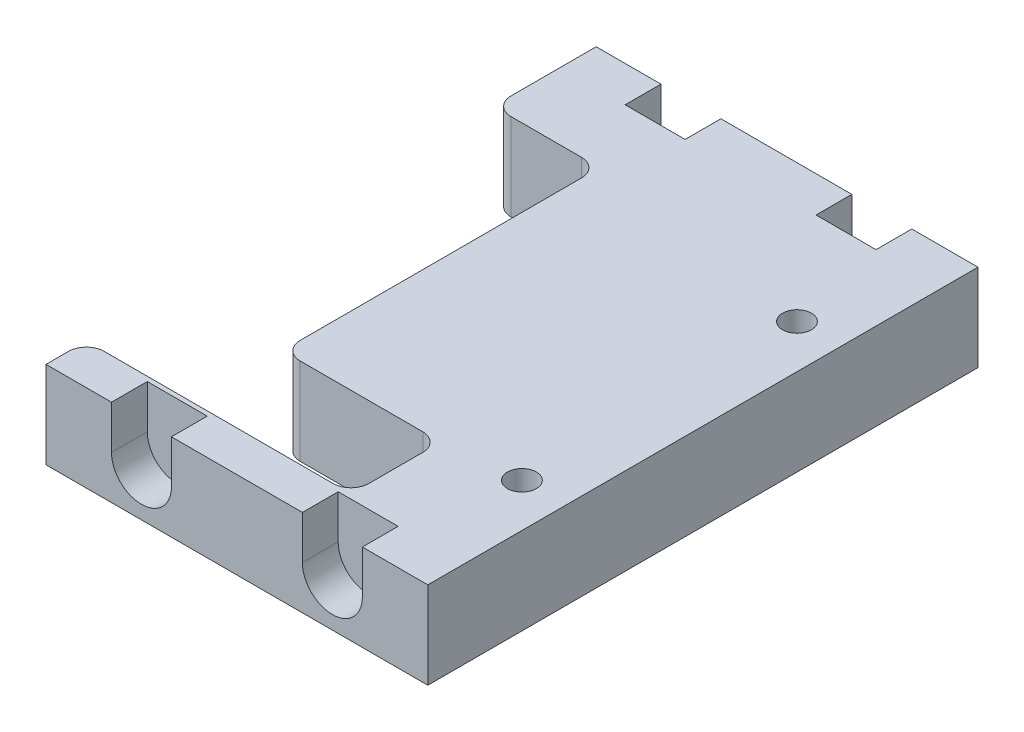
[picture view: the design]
ISO-10303-21;
HEADER;
FILE_DESCRIPTION(('STEP AP214'),'2;1');
FILE_NAME('part.step','',(''),(''),'','','');
FILE_SCHEMA(('AUTOMOTIVE_DESIGN { 1 0 10303 214 1 1 1 1 }'));
ENDSEC;
DATA;
#1=APPLICATION_CONTEXT('core data for automotive mechanical design processes');
#2=APPLICATION_PROTOCOL_DEFINITION('international standard','automotive_design',2000,#1);
#3=PRODUCT_CONTEXT('',#1,'mechanical');
#4=PRODUCT('Part','Part','',(#3));
#5=PRODUCT_RELATED_PRODUCT_CATEGORY('part','',(#4));
#6=PRODUCT_DEFINITION_FORMATION('','',#4);
#7=PRODUCT_DEFINITION_CONTEXT('part definition',#1,'design');
#8=PRODUCT_DEFINITION('design','',#6,#7);
#9=PRODUCT_DEFINITION_SHAPE('','',#8);
#10=(LENGTH_UNIT() NAMED_UNIT(*) SI_UNIT(.MILLI.,.METRE.));
#11=(NAMED_UNIT(*) PLANE_ANGLE_UNIT() SI_UNIT($,.RADIAN.));
#12=(NAMED_UNIT(*) SI_UNIT($,.STERADIAN.) SOLID_ANGLE_UNIT());
#13=UNCERTAINTY_MEASURE_WITH_UNIT(LENGTH_MEASURE(1.E-05),#10,'distance_accuracy_value','');
#14=(GEOMETRIC_REPRESENTATION_CONTEXT(3) GLOBAL_UNCERTAINTY_ASSIGNED_CONTEXT((#13)) GLOBAL_UNIT_ASSIGNED_CONTEXT((#10,
#11,#12)) REPRESENTATION_CONTEXT('',''));
#15=CARTESIAN_POINT('',(0.,0.,0.));
#16=DIRECTION('',(0.,0.,1.));
#17=DIRECTION('',(1.,0.,0.));
#18=AXIS2_PLACEMENT_3D('',#15,#16,#17);
#19=CARTESIAN_POINT('',(-654.083526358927,561.091856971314,0.));
#20=DIRECTION('',(0.,1.,0.));
#21=DIRECTION('',(0.,0.,1.));
#22=AXIS2_PLACEMENT_3D('',#19,#20,#21);
#23=PLANE('',#22);
#24=CARTESIAN_POINT('',(-726.128429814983,561.091856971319,-58.5596999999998));
#25=DIRECTION('',(0.,-1.,0.));
#26=DIRECTION('',(0.,0.,-1.));
#27=AXIS2_PLACEMENT_3D('',#24,#25,#26);
#28=CIRCLE('',#27,2.05000000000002);
#29=CARTESIAN_POINT('',(-726.128429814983,561.091856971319,-60.6096999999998));
#30=VERTEX_POINT('',#29);
#31=EDGE_CURVE('E428',#30,#30,#28,.F.);
#32=ORIENTED_EDGE('',*,*,#31,.F.);
#33=EDGE_LOOP('',(#32));
#34=FACE_BOUND('',#33,.T.);
#35=CARTESIAN_POINT('',(-726.128429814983,561.091856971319,-19.5198999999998));
#36=DIRECTION('',(0.,-1.,0.));
#37=DIRECTION('',(0.,0.,-1.));
#38=AXIS2_PLACEMENT_3D('',#35,#36,#37);
#39=CIRCLE('',#38,2.05000000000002);
#40=CARTESIAN_POINT('',(-726.128429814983,561.091856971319,-21.5698999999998));
#41=VERTEX_POINT('',#40);
#42=EDGE_CURVE('E392',#41,#41,#39,.F.);
#43=ORIENTED_EDGE('',*,*,#42,.F.);
#44=EDGE_LOOP('',(#43));
#45=FACE_BOUND('',#44,.T.);
#46=DIRECTION('',(1.,0.,0.));
#47=VECTOR('',#46,1.);
#48=CARTESIAN_POINT('',(-654.083526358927,561.091856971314,-78.0796));
#49=LINE('',#48,#47);
#50=CARTESIAN_POINT('',(-756.444899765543,561.091856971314,-78.0796));
#51=VERTEX_POINT('',#50);
#52=CARTESIAN_POINT('',(-737.859519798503,561.091856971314,-78.0796));
#53=VERTEX_POINT('',#52);
#54=EDGE_CURVE('E486',#51,#53,#49,.T.);
#55=ORIENTED_EDGE('',*,*,#54,.F.);
#56=DIRECTION('',(0.,0.,-1.));
#57=VECTOR('',#56,1.);
#58=CARTESIAN_POINT('',(-756.444899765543,561.091856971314,-72.9996));
#59=LINE('',#58,#57);
#60=CARTESIAN_POINT('',(-756.444899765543,561.091856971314,-72.9996));
#61=VERTEX_POINT('',#60);
#62=EDGE_CURVE('E340',#61,#51,#59,.T.);
#63=ORIENTED_EDGE('',*,*,#62,.F.);
#64=DIRECTION('',(1.,0.,0.));
#65=VECTOR('',#64,1.);
#66=CARTESIAN_POINT('',(0.,561.091856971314,-72.9996));
#67=LINE('',#66,#65);
#68=CARTESIAN_POINT('',(-764.953899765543,561.091856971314,-72.9996));
#69=VERTEX_POINT('',#68);
#70=EDGE_CURVE('E317',#69,#61,#67,.T.);
#71=ORIENTED_EDGE('',*,*,#70,.F.);
#72=DIRECTION('',(0.,0.,-1.));
#73=VECTOR('',#72,1.);
#74=CARTESIAN_POINT('',(-764.953899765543,561.091856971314,-72.9996));
#75=LINE('',#74,#73);
#76=CARTESIAN_POINT('',(-764.953899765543,561.091856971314,-78.0796));
#77=VERTEX_POINT('',#76);
#78=EDGE_CURVE('E312',#69,#77,#75,.T.);
#79=ORIENTED_EDGE('',*,*,#78,.T.);
#80=CARTESIAN_POINT('',(-774.144989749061,561.091856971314,-78.0796));
#81=VERTEX_POINT('',#80);
#82=EDGE_CURVE('E482',#81,#77,#49,.T.);
#83=ORIENTED_EDGE('',*,*,#82,.F.);
#84=DIRECTION('',(0.,0.,1.));
#85=VECTOR('',#84,1.);
#86=CARTESIAN_POINT('',(-774.144989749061,561.091856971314,0.));
#87=LINE('',#86,#85);
#88=CARTESIAN_POINT('',(-774.144989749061,561.091856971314,-65.9929986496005));
#89=VERTEX_POINT('',#88);
#90=EDGE_CURVE('E487',#81,#89,#87,.T.);
#91=ORIENTED_EDGE('',*,*,#90,.T.);
#92=CARTESIAN_POINT('',(-771.604989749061,561.091856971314,-65.9929986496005));
#93=DIRECTION('',(0.,1.,0.));
#94=DIRECTION('',(0.,0.,1.));
#95=AXIS2_PLACEMENT_3D('',#92,#93,#94);
#96=CIRCLE('',#95,2.54);
#97=CARTESIAN_POINT('',(-771.604989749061,561.091856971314,-63.4529986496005));
#98=VERTEX_POINT('',#97);
#99=EDGE_CURVE('E551',#89,#98,#96,.T.);
#100=ORIENTED_EDGE('',*,*,#99,.T.);
#101=DIRECTION('',(-1.,0.,0.));
#102=VECTOR('',#101,1.);
#103=CARTESIAN_POINT('',(0.,561.091856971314,-63.4529986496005));
#104=LINE('',#103,#102);
#105=CARTESIAN_POINT('',(-761.598172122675,561.091856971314,-63.4529986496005));
#106=VERTEX_POINT('',#105);
#107=EDGE_CURVE('E441',#106,#98,#104,.T.);
#108=ORIENTED_EDGE('',*,*,#107,.F.);
#109=CARTESIAN_POINT('',(-761.598172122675,561.091856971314,-60.9129986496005));
#110=DIRECTION('',(0.,1.,0.));
#111=DIRECTION('',(0.,0.,1.));
#112=AXIS2_PLACEMENT_3D('',#109,#110,#111);
#113=CIRCLE('',#112,2.54);
#114=CARTESIAN_POINT('',(-759.058172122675,561.091856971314,-60.9129986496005));
#115=VERTEX_POINT('',#114);
#116=EDGE_CURVE('E558',#106,#115,#113,.F.);
#117=ORIENTED_EDGE('',*,*,#116,.T.);
#118=DIRECTION('',(0.,0.,1.));
#119=VECTOR('',#118,1.);
#120=CARTESIAN_POINT('',(-759.058172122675,561.091856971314,0.));
#121=LINE('',#120,#119);
#122=CARTESIAN_POINT('',(-759.058172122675,561.091856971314,-20.995433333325));
#123=VERTEX_POINT('',#122);
#124=EDGE_CURVE('E435',#115,#123,#121,.T.);
#125=ORIENTED_EDGE('',*,*,#124,.T.);
#126=CARTESIAN_POINT('',(-756.518172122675,561.091856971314,-20.995433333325));
#127=DIRECTION('',(0.,1.,0.));
#128=DIRECTION('',(0.,0.,1.));
#129=AXIS2_PLACEMENT_3D('',#126,#127,#128);
#130=CIRCLE('',#129,2.54);
#131=CARTESIAN_POINT('',(-756.518172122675,561.091856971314,-18.455433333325));
#132=VERTEX_POINT('',#131);
#133=EDGE_CURVE('E519',#123,#132,#130,.T.);
#134=ORIENTED_EDGE('',*,*,#133,.T.);
#135=DIRECTION('',(-1.,0.,0.));
#136=VECTOR('',#135,1.);
#137=CARTESIAN_POINT('',(0.,561.091856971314,-18.455433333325));
#138=LINE('',#137,#136);
#139=CARTESIAN_POINT('',(-739.131574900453,561.091856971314,-18.455433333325));
#140=VERTEX_POINT('',#139);
#141=EDGE_CURVE('E437',#140,#132,#138,.T.);
#142=ORIENTED_EDGE('',*,*,#141,.F.);
#143=CARTESIAN_POINT('',(-739.131574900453,561.091856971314,-15.915433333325));
#144=DIRECTION('',(0.,1.,0.));
#145=DIRECTION('',(0.,0.,1.));
#146=AXIS2_PLACEMENT_3D('',#143,#144,#145);
#147=CIRCLE('',#146,2.54);
#148=CARTESIAN_POINT('',(-736.591574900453,561.091856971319,-15.915433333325));
#149=VERTEX_POINT('',#148);
#150=EDGE_CURVE('E536',#140,#149,#147,.F.);
#151=ORIENTED_EDGE('',*,*,#150,.T.);
#152=DIRECTION('',(0.,0.,-1.));
#153=VECTOR('',#152,1.);
#154=CARTESIAN_POINT('',(-736.591574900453,561.091856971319,0.));
#155=LINE('',#154,#153);
#156=CARTESIAN_POINT('',(-736.591574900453,561.091856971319,-8.26959999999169));
#157=VERTEX_POINT('',#156);
#158=EDGE_CURVE('E447',#157,#149,#155,.T.);
#159=ORIENTED_EDGE('',*,*,#158,.F.);
#160=CARTESIAN_POINT('',(-739.131574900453,561.091856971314,-8.26959999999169));
#161=DIRECTION('',(0.,1.,0.));
#162=DIRECTION('',(0.,0.,1.));
#163=AXIS2_PLACEMENT_3D('',#160,#161,#162);
#164=CIRCLE('',#163,2.54);
#165=CARTESIAN_POINT('',(-739.131574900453,561.091856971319,-5.72959999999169));
#166=VERTEX_POINT('',#165);
#167=EDGE_CURVE('E540',#157,#166,#164,.F.);
#168=ORIENTED_EDGE('',*,*,#167,.T.);
#169=DIRECTION('',(1.,0.,0.));
#170=VECTOR('',#169,1.);
#171=CARTESIAN_POINT('',(0.,561.091856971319,-5.72959999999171));
#172=LINE('',#171,#170);
#173=CARTESIAN_POINT('',(-771.604989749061,561.091856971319,-5.72959999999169));
#174=VERTEX_POINT('',#173);
#175=EDGE_CURVE('E452',#174,#166,#172,.T.);
#176=ORIENTED_EDGE('',*,*,#175,.F.);
#177=CARTESIAN_POINT('',(-771.604989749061,561.091856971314,-3.18959999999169));
#178=DIRECTION('',(0.,1.,0.));
#179=DIRECTION('',(0.,0.,1.));
#180=AXIS2_PLACEMENT_3D('',#177,#178,#179);
#181=CIRCLE('',#180,2.54);
#182=CARTESIAN_POINT('',(-774.144989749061,561.091856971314,-3.18959999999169));
#183=VERTEX_POINT('',#182);
#184=EDGE_CURVE('E517',#174,#183,#181,.T.);
#185=ORIENTED_EDGE('',*,*,#184,.T.);
#186=CARTESIAN_POINT('',(-774.144989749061,561.091856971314,0.));
#187=VERTEX_POINT('',#186);
#188=EDGE_CURVE('E491',#183,#187,#87,.T.);
#189=ORIENTED_EDGE('',*,*,#188,.T.);
#190=DIRECTION('',(-1.,0.,0.));
#191=VECTOR('',#190,1.);
#192=CARTESIAN_POINT('',(-654.083526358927,561.091856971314,0.));
#193=LINE('',#192,#191);
#194=CARTESIAN_POINT('',(-764.852299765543,561.091856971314,0.));
#195=VERTEX_POINT('',#194);
#196=EDGE_CURVE('E472',#195,#187,#193,.T.);
#197=ORIENTED_EDGE('',*,*,#196,.F.);
#198=DIRECTION('',(0.,0.,1.));
#199=VECTOR('',#198,1.);
#200=CARTESIAN_POINT('',(-764.852299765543,561.091856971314,-5.08));
#201=LINE('',#200,#199);
#202=CARTESIAN_POINT('',(-764.852299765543,561.091856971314,-5.08));
#203=VERTEX_POINT('',#202);
#204=EDGE_CURVE('E421',#203,#195,#201,.T.);
#205=ORIENTED_EDGE('',*,*,#204,.F.);
#206=DIRECTION('',(-1.,0.,0.));
#207=VECTOR('',#206,1.);
#208=CARTESIAN_POINT('',(0.,561.091856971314,-5.08));
#209=LINE('',#208,#207);
#210=CARTESIAN_POINT('',(-756.343299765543,561.091856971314,-5.08));
#211=VERTEX_POINT('',#210);
#212=EDGE_CURVE('E406',#211,#203,#209,.T.);
#213=ORIENTED_EDGE('',*,*,#212,.F.);
#214=DIRECTION('',(0.,0.,1.));
#215=VECTOR('',#214,1.);
#216=CARTESIAN_POINT('',(-756.343299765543,561.091856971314,-5.08));
#217=LINE('',#216,#215);
#218=CARTESIAN_POINT('',(-756.343299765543,561.091856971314,0.));
#219=VERTEX_POINT('',#218);
#220=EDGE_CURVE('E423',#211,#219,#217,.T.);
#221=ORIENTED_EDGE('',*,*,#220,.T.);
#222=CARTESIAN_POINT('',(-737.757919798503,561.091856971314,0.));
#223=VERTEX_POINT('',#222);
#224=EDGE_CURVE('E481',#223,#219,#193,.T.);
#225=ORIENTED_EDGE('',*,*,#224,.F.);
#226=DIRECTION('',(0.,0.,1.));
#227=VECTOR('',#226,1.);
#228=CARTESIAN_POINT('',(-737.757919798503,561.091856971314,-5.08));
#229=LINE('',#228,#227);
#230=CARTESIAN_POINT('',(-737.757919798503,561.091856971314,-5.08));
#231=VERTEX_POINT('',#230);
#232=EDGE_CURVE('E393',#231,#223,#229,.T.);
#233=ORIENTED_EDGE('',*,*,#232,.F.);
#234=DIRECTION('',(-1.,0.,0.));
#235=VECTOR('',#234,1.);
#236=CARTESIAN_POINT('',(0.,561.091856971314,-5.08));
#237=LINE('',#236,#235);
#238=CARTESIAN_POINT('',(-729.248919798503,561.091856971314,-5.08));
#239=VERTEX_POINT('',#238);
#240=EDGE_CURVE('E374',#239,#231,#237,.T.);
#241=ORIENTED_EDGE('',*,*,#240,.F.);
#242=DIRECTION('',(0.,0.,1.));
#243=VECTOR('',#242,1.);
#244=CARTESIAN_POINT('',(-729.248919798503,561.091856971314,-5.08));
#245=LINE('',#244,#243);
#246=CARTESIAN_POINT('',(-729.248919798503,561.091856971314,0.));
#247=VERTEX_POINT('',#246);
#248=EDGE_CURVE('E395',#239,#247,#245,.T.);
#249=ORIENTED_EDGE('',*,*,#248,.T.);
#250=CARTESIAN_POINT('',(-719.95622981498,561.091856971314,-2.2204460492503E-13));
#251=VERTEX_POINT('',#250);
#252=EDGE_CURVE('E477',#251,#247,#193,.T.);
#253=ORIENTED_EDGE('',*,*,#252,.F.);
#254=DIRECTION('',(0.,0.,-1.));
#255=VECTOR('',#254,1.);
#256=CARTESIAN_POINT('',(-719.95622981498,561.091856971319,2.22044604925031E-13));
#257=LINE('',#256,#255);
#258=CARTESIAN_POINT('',(-719.95622981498,561.091856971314,-78.0796000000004));
#259=VERTEX_POINT('',#258);
#260=EDGE_CURVE('E461',#251,#259,#257,.T.);
#261=ORIENTED_EDGE('',*,*,#260,.T.);
#262=CARTESIAN_POINT('',(-729.350519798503,561.091856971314,-78.0796));
#263=VERTEX_POINT('',#262);
#264=EDGE_CURVE('E480',#263,#259,#49,.T.);
#265=ORIENTED_EDGE('',*,*,#264,.F.);
#266=DIRECTION('',(0.,0.,-1.));
#267=VECTOR('',#266,1.);
#268=CARTESIAN_POINT('',(-729.350519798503,561.091856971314,-72.9996));
#269=LINE('',#268,#267);
#270=CARTESIAN_POINT('',(-729.350519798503,561.091856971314,-72.9996));
#271=VERTEX_POINT('',#270);
#272=EDGE_CURVE('E362',#271,#263,#269,.T.);
#273=ORIENTED_EDGE('',*,*,#272,.F.);
#274=DIRECTION('',(1.,0.,0.));
#275=VECTOR('',#274,1.);
#276=CARTESIAN_POINT('',(0.,561.091856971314,-72.9996));
#277=LINE('',#276,#275);
#278=CARTESIAN_POINT('',(-737.859519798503,561.091856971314,-72.9996));
#279=VERTEX_POINT('',#278);
#280=EDGE_CURVE('E349',#279,#271,#277,.T.);
#281=ORIENTED_EDGE('',*,*,#280,.F.);
#282=DIRECTION('',(0.,0.,-1.));
#283=VECTOR('',#282,1.);
#284=CARTESIAN_POINT('',(-737.859519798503,561.091856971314,-72.9996));
#285=LINE('',#284,#283);
#286=EDGE_CURVE('E364',#279,#53,#285,.T.);
#287=ORIENTED_EDGE('',*,*,#286,.T.);
#288=EDGE_LOOP('',(#55,#63,#71,#79,#83,#91,#100,#108,#117,#125,#134,#142,#151,#159,#168,#176,
#185,#189,#197,#205,#213,#221,#225,#233,#241,#249,#253,#261,#265,#273,#281,#287));
#289=FACE_BOUND('',#288,.T.);
#290=ADVANCED_FACE('F94',(#34,#45,#289),#23,.T.);
#291=CARTESIAN_POINT('',(-1553.36997949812,0.,-78.0796));
#292=DIRECTION('',(0.,0.,-1.));
#293=DIRECTION('',(1.,0.,0.));
#294=AXIS2_PLACEMENT_3D('',#291,#292,#293);
#295=PLANE('',#294);
#296=CARTESIAN_POINT('',(-760.699399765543,554.919656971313,-78.0796));
#297=DIRECTION('',(0.,0.,-1.));
#298=DIRECTION('',(-1.,0.,0.));
#299=AXIS2_PLACEMENT_3D('',#296,#297,#298);
#300=CIRCLE('',#299,4.25450000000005);
#301=CARTESIAN_POINT('',(-764.953899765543,554.919656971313,-78.0796));
#302=VERTEX_POINT('',#301);
#303=CARTESIAN_POINT('',(-756.444899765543,554.919656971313,-78.0796));
#304=VERTEX_POINT('',#303);
#305=EDGE_CURVE('E110',#302,#304,#300,.F.);
#306=ORIENTED_EDGE('',*,*,#305,.T.);
#307=DIRECTION('',(0.,1.,0.));
#308=VECTOR('',#307,1.);
#309=CARTESIAN_POINT('',(-756.444899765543,0.,-78.0796));
#310=LINE('',#309,#308);
#311=EDGE_CURVE('E326',#304,#51,#310,.T.);
#312=ORIENTED_EDGE('',*,*,#311,.T.);
#313=ORIENTED_EDGE('',*,*,#54,.T.);
#314=DIRECTION('',(0.,-1.,0.));
#315=VECTOR('',#314,1.);
#316=CARTESIAN_POINT('',(-737.859519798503,0.,-78.0796));
#317=LINE('',#316,#315);
#318=CARTESIAN_POINT('',(-737.859519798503,554.919656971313,-78.0796));
#319=VERTEX_POINT('',#318);
#320=EDGE_CURVE('E356',#53,#319,#317,.T.);
#321=ORIENTED_EDGE('',*,*,#320,.T.);
#322=CARTESIAN_POINT('',(-733.605019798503,554.919656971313,-78.0796));
#323=DIRECTION('',(0.,0.,-1.));
#324=DIRECTION('',(-1.,0.,0.));
#325=AXIS2_PLACEMENT_3D('',#322,#323,#324);
#326=CIRCLE('',#325,4.25450000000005);
#327=CARTESIAN_POINT('',(-729.350519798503,554.919656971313,-78.0796));
#328=VERTEX_POINT('',#327);
#329=EDGE_CURVE('E118',#319,#328,#326,.F.);
#330=ORIENTED_EDGE('',*,*,#329,.T.);
#331=DIRECTION('',(0.,1.,0.));
#332=VECTOR('',#331,1.);
#333=CARTESIAN_POINT('',(-729.350519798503,0.,-78.0796));
#334=LINE('',#333,#332);
#335=EDGE_CURVE('E347',#328,#263,#334,.T.);
#336=ORIENTED_EDGE('',*,*,#335,.T.);
#337=ORIENTED_EDGE('',*,*,#264,.T.);
#338=DIRECTION('',(0.,1.,0.));
#339=VECTOR('',#338,1.);
#340=CARTESIAN_POINT('',(-719.956229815,2.51751805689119E-11,-78.0796));
#341=LINE('',#340,#339);
#342=CARTESIAN_POINT('',(-719.95622981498,548.747456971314,-78.0796));
#343=VERTEX_POINT('',#342);
#344=EDGE_CURVE('E465',#343,#259,#341,.T.);
#345=ORIENTED_EDGE('',*,*,#344,.F.);
#346=DIRECTION('',(1.,0.,0.));
#347=VECTOR('',#346,1.);
#348=CARTESIAN_POINT('',(0.,548.747456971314,-78.0796));
#349=LINE('',#348,#347);
#350=CARTESIAN_POINT('',(-774.144989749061,548.747456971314,-78.0796));
#351=VERTEX_POINT('',#350);
#352=EDGE_CURVE('E468',#351,#343,#349,.T.);
#353=ORIENTED_EDGE('',*,*,#352,.F.);
#354=DIRECTION('',(0.,-1.,0.));
#355=VECTOR('',#354,1.);
#356=CARTESIAN_POINT('',(-774.144989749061,562.158656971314,-78.0796));
#357=LINE('',#356,#355);
#358=EDGE_CURVE('E490',#81,#351,#357,.T.);
#359=ORIENTED_EDGE('',*,*,#358,.F.);
#360=ORIENTED_EDGE('',*,*,#82,.T.);
#361=DIRECTION('',(0.,-1.,0.));
#362=VECTOR('',#361,1.);
#363=CARTESIAN_POINT('',(-764.953899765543,0.,-78.0796));
#364=LINE('',#363,#362);
#365=EDGE_CURVE('E329',#77,#302,#364,.T.);
#366=ORIENTED_EDGE('',*,*,#365,.T.);
#367=EDGE_LOOP('',(#306,#312,#313,#321,#330,#336,#337,#345,#353,#359,#360,#366));
#368=FACE_BOUND('',#367,.T.);
#369=ADVANCED_FACE('F688',(#368),#295,.T.);
#370=CARTESIAN_POINT('',(-1553.36997949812,0.,0.));
#371=DIRECTION('',(0.,0.,1.));
#372=DIRECTION('',(-1.,0.,0.));
#373=AXIS2_PLACEMENT_3D('',#370,#371,#372);
#374=PLANE('',#373);
#375=CARTESIAN_POINT('',(-733.503419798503,554.919656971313,0.));
#376=DIRECTION('',(0.,0.,1.));
#377=DIRECTION('',(1.,0.,0.));
#378=AXIS2_PLACEMENT_3D('',#375,#376,#377);
#379=CIRCLE('',#378,4.25450000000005);
#380=CARTESIAN_POINT('',(-729.248919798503,554.919656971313,0.));
#381=VERTEX_POINT('',#380);
#382=CARTESIAN_POINT('',(-737.757919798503,554.919656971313,0.));
#383=VERTEX_POINT('',#382);
#384=EDGE_CURVE('E380',#381,#383,#379,.F.);
#385=ORIENTED_EDGE('',*,*,#384,.T.);
#386=DIRECTION('',(0.,1.,0.));
#387=VECTOR('',#386,1.);
#388=CARTESIAN_POINT('',(-737.757919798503,0.,0.));
#389=LINE('',#388,#387);
#390=EDGE_CURVE('E372',#383,#223,#389,.T.);
#391=ORIENTED_EDGE('',*,*,#390,.T.);
#392=ORIENTED_EDGE('',*,*,#224,.T.);
#393=DIRECTION('',(0.,-1.,0.));
#394=VECTOR('',#393,1.);
#395=CARTESIAN_POINT('',(-756.343299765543,0.,0.));
#396=LINE('',#395,#394);
#397=CARTESIAN_POINT('',(-756.343299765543,554.919656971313,0.));
#398=VERTEX_POINT('',#397);
#399=EDGE_CURVE('E414',#219,#398,#396,.T.);
#400=ORIENTED_EDGE('',*,*,#399,.T.);
#401=CARTESIAN_POINT('',(-760.597799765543,554.919656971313,0.));
#402=DIRECTION('',(0.,0.,1.));
#403=DIRECTION('',(1.,0.,0.));
#404=AXIS2_PLACEMENT_3D('',#401,#402,#403);
#405=CIRCLE('',#404,4.25450000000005);
#406=CARTESIAN_POINT('',(-764.852299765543,554.919656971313,0.));
#407=VERTEX_POINT('',#406);
#408=EDGE_CURVE('E339',#398,#407,#405,.F.);
#409=ORIENTED_EDGE('',*,*,#408,.T.);
#410=DIRECTION('',(0.,1.,0.));
#411=VECTOR('',#410,1.);
#412=CARTESIAN_POINT('',(-764.852299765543,0.,0.));
#413=LINE('',#412,#411);
#414=EDGE_CURVE('E404',#407,#195,#413,.T.);
#415=ORIENTED_EDGE('',*,*,#414,.T.);
#416=ORIENTED_EDGE('',*,*,#196,.T.);
#417=DIRECTION('',(0.,-1.,0.));
#418=VECTOR('',#417,1.);
#419=CARTESIAN_POINT('',(-774.144989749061,0.,0.));
#420=LINE('',#419,#418);
#421=CARTESIAN_POINT('',(-774.144989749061,548.747456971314,2.22044604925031E-13));
#422=VERTEX_POINT('',#421);
#423=EDGE_CURVE('E498',#187,#422,#420,.T.);
#424=ORIENTED_EDGE('',*,*,#423,.T.);
#425=DIRECTION('',(-1.,0.,0.));
#426=VECTOR('',#425,1.);
#427=CARTESIAN_POINT('',(105.83751986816,548.747456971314,2.22044604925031E-13));
#428=LINE('',#427,#426);
#429=CARTESIAN_POINT('',(-719.95622981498,548.747456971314,2.22044604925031E-13));
#430=VERTEX_POINT('',#429);
#431=EDGE_CURVE('E469',#430,#422,#428,.T.);
#432=ORIENTED_EDGE('',*,*,#431,.F.);
#433=DIRECTION('',(0.,-1.,0.));
#434=VECTOR('',#433,1.);
#435=CARTESIAN_POINT('',(-719.956229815,2.39355779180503E-11,2.22044604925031E-13));
#436=LINE('',#435,#434);
#437=EDGE_CURVE('E464',#251,#430,#436,.T.);
#438=ORIENTED_EDGE('',*,*,#437,.F.);
#439=ORIENTED_EDGE('',*,*,#252,.T.);
#440=DIRECTION('',(0.,-1.,0.));
#441=VECTOR('',#440,1.);
#442=CARTESIAN_POINT('',(-729.248919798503,0.,0.));
#443=LINE('',#442,#441);
#444=EDGE_CURVE('E383',#247,#381,#443,.T.);
#445=ORIENTED_EDGE('',*,*,#444,.T.);
#446=EDGE_LOOP('',(#385,#391,#392,#400,#409,#415,#416,#424,#432,#438,#439,#445));
#447=FACE_BOUND('',#446,.T.);
#448=ADVANCED_FACE('F640',(#447),#374,.T.);
#449=CARTESIAN_POINT('',(0.,584.209465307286,-63.4529986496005));
#450=DIRECTION('',(0.,0.,1.));
#451=DIRECTION('',(1.,0.,0.));
#452=AXIS2_PLACEMENT_3D('',#449,#450,#451);
#453=PLANE('',#452);
#454=ORIENTED_EDGE('',*,*,#107,.T.);
#455=DIRECTION('',(0.,-1.,0.));
#456=VECTOR('',#455,1.);
#457=CARTESIAN_POINT('',(-771.604989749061,584.209465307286,-63.4529986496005));
#458=LINE('',#457,#456);
#459=CARTESIAN_POINT('',(-771.604989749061,548.747456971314,-63.4529986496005));
#460=VERTEX_POINT('',#459);
#461=EDGE_CURVE('E544',#98,#460,#458,.T.);
#462=ORIENTED_EDGE('',*,*,#461,.T.);
#463=DIRECTION('',(-1.,0.,0.));
#464=VECTOR('',#463,1.);
#465=CARTESIAN_POINT('',(0.,548.747456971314,-63.4529986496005));
#466=LINE('',#465,#464);
#467=CARTESIAN_POINT('',(-761.598172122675,548.747456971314,-63.4529986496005));
#468=VERTEX_POINT('',#467);
#469=EDGE_CURVE('E444',#468,#460,#466,.T.);
#470=ORIENTED_EDGE('',*,*,#469,.F.);
#471=DIRECTION('',(0.,-1.,0.));
#472=VECTOR('',#471,1.);
#473=CARTESIAN_POINT('',(-761.598172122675,584.209465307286,-63.4529986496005));
#474=LINE('',#473,#472);
#475=EDGE_CURVE('E542',#468,#106,#474,.F.);
#476=ORIENTED_EDGE('',*,*,#475,.T.);
#477=EDGE_LOOP('',(#454,#462,#470,#476));
#478=FACE_BOUND('',#477,.T.);
#479=ADVANCED_FACE('F581',(#478),#453,.T.);
#480=CARTESIAN_POINT('',(-1553.36997949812,548.747456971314,0.));
#481=DIRECTION('',(0.,-1.,0.));
#482=DIRECTION('',(0.,0.,-1.));
#483=AXIS2_PLACEMENT_3D('',#480,#481,#482);
#484=PLANE('',#483);
#485=CARTESIAN_POINT('',(-726.128429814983,548.747456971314,-19.5198999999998));
#486=DIRECTION('',(0.,-1.,0.));
#487=DIRECTION('',(0.,0.,-1.));
#488=AXIS2_PLACEMENT_3D('',#485,#486,#487);
#489=CIRCLE('',#488,3.31999999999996);
#490=CARTESIAN_POINT('',(-726.128429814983,548.747456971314,-22.8398999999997));
#491=VERTEX_POINT('',#490);
#492=EDGE_CURVE('E563',#491,#491,#489,.F.);
#493=ORIENTED_EDGE('',*,*,#492,.T.);
#494=EDGE_LOOP('',(#493));
#495=FACE_BOUND('',#494,.T.);
#496=CARTESIAN_POINT('',(-726.128429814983,548.747456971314,-58.5596999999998));
#497=DIRECTION('',(0.,-1.,0.));
#498=DIRECTION('',(0.,0.,-1.));
#499=AXIS2_PLACEMENT_3D('',#496,#497,#498);
#500=CIRCLE('',#499,3.31999999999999);
#501=CARTESIAN_POINT('',(-726.128429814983,548.747456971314,-61.8796999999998));
#502=VERTEX_POINT('',#501);
#503=EDGE_CURVE('E560',#502,#502,#500,.F.);
#504=ORIENTED_EDGE('',*,*,#503,.T.);
#505=EDGE_LOOP('',(#504));
#506=FACE_BOUND('',#505,.T.);
#507=ORIENTED_EDGE('',*,*,#469,.T.);
#508=CARTESIAN_POINT('',(-771.604989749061,548.747456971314,-65.9929986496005));
#509=DIRECTION('',(0.,-1.,0.));
#510=DIRECTION('',(0.,0.,-1.));
#511=AXIS2_PLACEMENT_3D('',#508,#509,#510);
#512=CIRCLE('',#511,2.54);
#513=CARTESIAN_POINT('',(-774.144989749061,548.747456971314,-65.9929986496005));
#514=VERTEX_POINT('',#513);
#515=EDGE_CURVE('E547',#460,#514,#512,.T.);
#516=ORIENTED_EDGE('',*,*,#515,.T.);
#517=DIRECTION('',(0.,0.,1.));
#518=VECTOR('',#517,1.);
#519=CARTESIAN_POINT('',(-774.144989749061,548.747456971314,-84.4296));
#520=LINE('',#519,#518);
#521=EDGE_CURVE('E492',#351,#514,#520,.T.);
#522=ORIENTED_EDGE('',*,*,#521,.F.);
#523=ORIENTED_EDGE('',*,*,#352,.T.);
#524=DIRECTION('',(0.,0.,1.));
#525=VECTOR('',#524,1.);
#526=CARTESIAN_POINT('',(-719.95622981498,548.747456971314,-84.4296));
#527=LINE('',#526,#525);
#528=EDGE_CURVE('E495',#343,#430,#527,.T.);
#529=ORIENTED_EDGE('',*,*,#528,.T.);
#530=ORIENTED_EDGE('',*,*,#431,.T.);
#531=CARTESIAN_POINT('',(-774.144989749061,548.747456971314,-3.18959999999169));
#532=VERTEX_POINT('',#531);
#533=EDGE_CURVE('E485',#532,#422,#520,.T.);
#534=ORIENTED_EDGE('',*,*,#533,.F.);
#535=CARTESIAN_POINT('',(-771.604989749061,548.747456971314,-3.18959999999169));
#536=DIRECTION('',(0.,-1.,0.));
#537=DIRECTION('',(0.,0.,-1.));
#538=AXIS2_PLACEMENT_3D('',#535,#536,#537);
#539=CIRCLE('',#538,2.54);
#540=CARTESIAN_POINT('',(-771.604989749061,548.747456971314,-5.72959999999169));
#541=VERTEX_POINT('',#540);
#542=EDGE_CURVE('E509',#532,#541,#539,.T.);
#543=ORIENTED_EDGE('',*,*,#542,.T.);
#544=DIRECTION('',(1.,0.,0.));
#545=VECTOR('',#544,1.);
#546=CARTESIAN_POINT('',(-1553.36997949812,548.747456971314,-5.72959999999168));
#547=LINE('',#546,#545);
#548=CARTESIAN_POINT('',(-739.131574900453,548.747456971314,-5.72959999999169));
#549=VERTEX_POINT('',#548);
#550=EDGE_CURVE('E455',#541,#549,#547,.T.);
#551=ORIENTED_EDGE('',*,*,#550,.T.);
#552=CARTESIAN_POINT('',(-739.131574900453,548.747456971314,-8.26959999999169));
#553=DIRECTION('',(0.,-1.,0.));
#554=DIRECTION('',(0.,0.,-1.));
#555=AXIS2_PLACEMENT_3D('',#552,#553,#554);
#556=CIRCLE('',#555,2.54);
#557=CARTESIAN_POINT('',(-736.591574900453,548.747456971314,-8.26959999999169));
#558=VERTEX_POINT('',#557);
#559=EDGE_CURVE('E538',#549,#558,#556,.F.);
#560=ORIENTED_EDGE('',*,*,#559,.T.);
#561=DIRECTION('',(0.,0.,-1.));
#562=VECTOR('',#561,1.);
#563=CARTESIAN_POINT('',(-736.591574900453,548.747456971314,0.));
#564=LINE('',#563,#562);
#565=CARTESIAN_POINT('',(-736.591574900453,548.747456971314,-15.915433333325));
#566=VERTEX_POINT('',#565);
#567=EDGE_CURVE('E458',#558,#566,#564,.T.);
#568=ORIENTED_EDGE('',*,*,#567,.T.);
#569=CARTESIAN_POINT('',(-739.131574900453,548.747456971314,-15.915433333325));
#570=DIRECTION('',(0.,-1.,0.));
#571=DIRECTION('',(0.,0.,-1.));
#572=AXIS2_PLACEMENT_3D('',#569,#570,#571);
#573=CIRCLE('',#572,2.54);
#574=CARTESIAN_POINT('',(-739.131574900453,548.747456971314,-18.455433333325));
#575=VERTEX_POINT('',#574);
#576=EDGE_CURVE('E534',#566,#575,#573,.F.);
#577=ORIENTED_EDGE('',*,*,#576,.T.);
#578=DIRECTION('',(-1.,0.,0.));
#579=VECTOR('',#578,1.);
#580=CARTESIAN_POINT('',(0.,548.747456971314,-18.455433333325));
#581=LINE('',#580,#579);
#582=CARTESIAN_POINT('',(-756.518172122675,548.747456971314,-18.455433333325));
#583=VERTEX_POINT('',#582);
#584=EDGE_CURVE('E438',#575,#583,#581,.T.);
#585=ORIENTED_EDGE('',*,*,#584,.T.);
#586=CARTESIAN_POINT('',(-756.518172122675,548.747456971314,-20.995433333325));
#587=DIRECTION('',(0.,-1.,0.));
#588=DIRECTION('',(0.,0.,-1.));
#589=AXIS2_PLACEMENT_3D('',#586,#587,#588);
#590=CIRCLE('',#589,2.54);
#591=CARTESIAN_POINT('',(-759.058172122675,548.747456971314,-20.995433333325));
#592=VERTEX_POINT('',#591);
#593=EDGE_CURVE('E511',#583,#592,#590,.T.);
#594=ORIENTED_EDGE('',*,*,#593,.T.);
#595=DIRECTION('',(0.,0.,1.));
#596=VECTOR('',#595,1.);
#597=CARTESIAN_POINT('',(-759.058172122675,548.747456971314,0.));
#598=LINE('',#597,#596);
#599=CARTESIAN_POINT('',(-759.058172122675,548.747456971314,-60.9129986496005));
#600=VERTEX_POINT('',#599);
#601=EDGE_CURVE('E431',#600,#592,#598,.T.);
#602=ORIENTED_EDGE('',*,*,#601,.F.);
#603=CARTESIAN_POINT('',(-761.598172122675,548.747456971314,-60.9129986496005));
#604=DIRECTION('',(0.,-1.,0.));
#605=DIRECTION('',(0.,0.,-1.));
#606=AXIS2_PLACEMENT_3D('',#603,#604,#605);
#607=CIRCLE('',#606,2.54);
#608=EDGE_CURVE('E556',#600,#468,#607,.F.);
#609=ORIENTED_EDGE('',*,*,#608,.T.);
#610=EDGE_LOOP('',(#507,#516,#522,#523,#529,#530,#534,#543,#551,#560,#568,#577,#585,#594,#602,#609));
#611=FACE_BOUND('',#610,.T.);
#612=ADVANCED_FACE('F577',(#495,#506,#611),#484,.T.);
#613=CARTESIAN_POINT('',(-774.144989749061,0.,6.35));
#614=DIRECTION('',(-1.,0.,0.));
#615=DIRECTION('',(0.,0.,-1.));
#616=AXIS2_PLACEMENT_3D('',#613,#614,#615);
#617=PLANE('',#616);
#618=ORIENTED_EDGE('',*,*,#188,.F.);
#619=DIRECTION('',(0.,-1.,0.));
#620=VECTOR('',#619,1.);
#621=CARTESIAN_POINT('',(-774.144989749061,0.,-3.18959999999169));
#622=LINE('',#621,#620);
#623=EDGE_CURVE('E531',#183,#532,#622,.T.);
#624=ORIENTED_EDGE('',*,*,#623,.T.);
#625=ORIENTED_EDGE('',*,*,#533,.T.);
#626=ORIENTED_EDGE('',*,*,#423,.F.);
#627=EDGE_LOOP('',(#618,#624,#625,#626));
#628=FACE_BOUND('',#627,.T.);
#629=ADVANCED_FACE('F580',(#628),#617,.T.);
#630=CARTESIAN_POINT('',(-719.95622981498,0.,0.));
#631=DIRECTION('',(1.,0.,0.));
#632=DIRECTION('',(0.,0.,1.));
#633=AXIS2_PLACEMENT_3D('',#630,#631,#632);
#634=PLANE('',#633);
#635=ORIENTED_EDGE('',*,*,#528,.F.);
#636=ORIENTED_EDGE('',*,*,#344,.T.);
#637=ORIENTED_EDGE('',*,*,#260,.F.);
#638=ORIENTED_EDGE('',*,*,#437,.T.);
#639=EDGE_LOOP('',(#635,#636,#637,#638));
#640=FACE_BOUND('',#639,.T.);
#641=ADVANCED_FACE('F645',(#640),#634,.T.);
#642=ORIENTED_EDGE('',*,*,#521,.T.);
#643=DIRECTION('',(0.,-1.,0.));
#644=VECTOR('',#643,1.);
#645=CARTESIAN_POINT('',(-774.144989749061,0.,-65.9929986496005));
#646=LINE('',#645,#644);
#647=EDGE_CURVE('E549',#514,#89,#646,.F.);
#648=ORIENTED_EDGE('',*,*,#647,.T.);
#649=ORIENTED_EDGE('',*,*,#90,.F.);
#650=ORIENTED_EDGE('',*,*,#358,.T.);
#651=EDGE_LOOP('',(#642,#648,#649,#650));
#652=FACE_BOUND('',#651,.T.);
#653=ADVANCED_FACE('F737',(#652),#617,.T.);
#654=CARTESIAN_POINT('',(0.,561.091856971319,-5.72959999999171));
#655=DIRECTION('',(0.,0.,-1.));
#656=DIRECTION('',(-1.,0.,0.));
#657=AXIS2_PLACEMENT_3D('',#654,#655,#656);
#658=PLANE('',#657);
#659=ORIENTED_EDGE('',*,*,#175,.T.);
#660=DIRECTION('',(0.,-1.,0.));
#661=VECTOR('',#660,1.);
#662=CARTESIAN_POINT('',(-739.131574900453,548.747456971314,-5.72959999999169));
#663=LINE('',#662,#661);
#664=EDGE_CURVE('E528',#166,#549,#663,.T.);
#665=ORIENTED_EDGE('',*,*,#664,.T.);
#666=ORIENTED_EDGE('',*,*,#550,.F.);
#667=DIRECTION('',(0.,-1.,0.));
#668=VECTOR('',#667,1.);
#669=CARTESIAN_POINT('',(-771.604989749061,561.091856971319,-5.72959999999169));
#670=LINE('',#669,#668);
#671=EDGE_CURVE('E526',#541,#174,#670,.F.);
#672=ORIENTED_EDGE('',*,*,#671,.T.);
#673=EDGE_LOOP('',(#659,#665,#666,#672));
#674=FACE_BOUND('',#673,.T.);
#675=ADVANCED_FACE('F627',(#674),#658,.T.);
#676=CARTESIAN_POINT('',(-736.591574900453,561.091856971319,0.));
#677=DIRECTION('',(-1.,0.,0.));
#678=DIRECTION('',(0.,0.,1.));
#679=AXIS2_PLACEMENT_3D('',#676,#677,#678);
#680=PLANE('',#679);
#681=ORIENTED_EDGE('',*,*,#158,.T.);
#682=DIRECTION('',(0.,-1.,0.));
#683=VECTOR('',#682,1.);
#684=CARTESIAN_POINT('',(-736.591574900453,548.747456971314,-15.915433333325));
#685=LINE('',#684,#683);
#686=EDGE_CURVE('E523',#149,#566,#685,.T.);
#687=ORIENTED_EDGE('',*,*,#686,.T.);
#688=ORIENTED_EDGE('',*,*,#567,.F.);
#689=DIRECTION('',(0.,-1.,0.));
#690=VECTOR('',#689,1.);
#691=CARTESIAN_POINT('',(-736.591574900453,561.091856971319,-8.26959999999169));
#692=LINE('',#691,#690);
#693=EDGE_CURVE('E521',#558,#157,#692,.F.);
#694=ORIENTED_EDGE('',*,*,#693,.T.);
#695=EDGE_LOOP('',(#681,#687,#688,#694));
#696=FACE_BOUND('',#695,.T.);
#697=ADVANCED_FACE('F618',(#696),#680,.T.);
#698=CARTESIAN_POINT('',(0.,576.92512934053,-18.455433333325));
#699=DIRECTION('',(0.,0.,1.));
#700=DIRECTION('',(1.,0.,0.));
#701=AXIS2_PLACEMENT_3D('',#698,#699,#700);
#702=PLANE('',#701);
#703=ORIENTED_EDGE('',*,*,#141,.T.);
#704=DIRECTION('',(0.,-1.,0.));
#705=VECTOR('',#704,1.);
#706=CARTESIAN_POINT('',(-756.518172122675,548.747456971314,-18.455433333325));
#707=LINE('',#706,#705);
#708=EDGE_CURVE('E506',#132,#583,#707,.T.);
#709=ORIENTED_EDGE('',*,*,#708,.T.);
#710=ORIENTED_EDGE('',*,*,#584,.F.);
#711=DIRECTION('',(0.,-1.,0.));
#712=VECTOR('',#711,1.);
#713=CARTESIAN_POINT('',(-739.131574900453,561.091856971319,-18.455433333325));
#714=LINE('',#713,#712);
#715=EDGE_CURVE('E501',#575,#140,#714,.F.);
#716=ORIENTED_EDGE('',*,*,#715,.T.);
#717=EDGE_LOOP('',(#703,#709,#710,#716));
#718=FACE_BOUND('',#717,.T.);
#719=ADVANCED_FACE('F609',(#718),#702,.T.);
#720=CARTESIAN_POINT('',(-759.058172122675,606.797770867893,0.));
#721=DIRECTION('',(1.,0.,0.));
#722=DIRECTION('',(0.,0.,-1.));
#723=AXIS2_PLACEMENT_3D('',#720,#721,#722);
#724=PLANE('',#723);
#725=ORIENTED_EDGE('',*,*,#124,.F.);
#726=DIRECTION('',(0.,-1.,0.));
#727=VECTOR('',#726,1.);
#728=CARTESIAN_POINT('',(-759.058172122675,606.797770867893,-60.9129986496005));
#729=LINE('',#728,#727);
#730=EDGE_CURVE('E553',#115,#600,#729,.T.);
#731=ORIENTED_EDGE('',*,*,#730,.T.);
#732=ORIENTED_EDGE('',*,*,#601,.T.);
#733=DIRECTION('',(0.,-1.,0.));
#734=VECTOR('',#733,1.);
#735=CARTESIAN_POINT('',(-759.058172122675,561.091856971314,-20.995433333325));
#736=LINE('',#735,#734);
#737=EDGE_CURVE('E514',#592,#123,#736,.F.);
#738=ORIENTED_EDGE('',*,*,#737,.T.);
#739=EDGE_LOOP('',(#725,#731,#732,#738));
#740=FACE_BOUND('',#739,.T.);
#741=ADVANCED_FACE('F600',(#740),#724,.F.);
#742=CARTESIAN_POINT('',(-756.518172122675,576.92512934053,-20.995433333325));
#743=DIRECTION('',(0.,1.,0.));
#744=DIRECTION('',(0.,0.,1.));
#745=AXIS2_PLACEMENT_3D('',#742,#743,#744);
#746=CYLINDRICAL_SURFACE('',#745,2.54);
#747=ORIENTED_EDGE('',*,*,#133,.F.);
#748=ORIENTED_EDGE('',*,*,#737,.F.);
#749=ORIENTED_EDGE('',*,*,#593,.F.);
#750=ORIENTED_EDGE('',*,*,#708,.F.);
#751=EDGE_LOOP('',(#747,#748,#749,#750));
#752=FACE_BOUND('',#751,.T.);
#753=ADVANCED_FACE('F605',(#752),#746,.T.);
#754=CARTESIAN_POINT('',(-739.131574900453,561.091856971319,-15.915433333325));
#755=DIRECTION('',(0.,1.,0.));
#756=DIRECTION('',(0.,0.,1.));
#757=AXIS2_PLACEMENT_3D('',#754,#755,#756);
#758=CYLINDRICAL_SURFACE('',#757,2.54);
#759=ORIENTED_EDGE('',*,*,#150,.F.);
#760=ORIENTED_EDGE('',*,*,#715,.F.);
#761=ORIENTED_EDGE('',*,*,#576,.F.);
#762=ORIENTED_EDGE('',*,*,#686,.F.);
#763=EDGE_LOOP('',(#759,#760,#761,#762));
#764=FACE_BOUND('',#763,.T.);
#765=ADVANCED_FACE('F613',(#764),#758,.F.);
#766=CARTESIAN_POINT('',(-739.131574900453,561.091856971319,-8.26959999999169));
#767=DIRECTION('',(0.,1.,0.));
#768=DIRECTION('',(0.,0.,1.));
#769=AXIS2_PLACEMENT_3D('',#766,#767,#768);
#770=CYLINDRICAL_SURFACE('',#769,2.54);
#771=ORIENTED_EDGE('',*,*,#167,.F.);
#772=ORIENTED_EDGE('',*,*,#693,.F.);
#773=ORIENTED_EDGE('',*,*,#559,.F.);
#774=ORIENTED_EDGE('',*,*,#664,.F.);
#775=EDGE_LOOP('',(#771,#772,#773,#774));
#776=FACE_BOUND('',#775,.T.);
#777=ADVANCED_FACE('F622',(#776),#770,.F.);
#778=CARTESIAN_POINT('',(-771.604989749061,0.,-3.18959999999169));
#779=DIRECTION('',(0.,-1.,0.));
#780=DIRECTION('',(0.,0.,-1.));
#781=AXIS2_PLACEMENT_3D('',#778,#779,#780);
#782=CYLINDRICAL_SURFACE('',#781,2.54);
#783=ORIENTED_EDGE('',*,*,#184,.F.);
#784=ORIENTED_EDGE('',*,*,#671,.F.);
#785=ORIENTED_EDGE('',*,*,#542,.F.);
#786=ORIENTED_EDGE('',*,*,#623,.F.);
#787=EDGE_LOOP('',(#783,#784,#785,#786));
#788=FACE_BOUND('',#787,.T.);
#789=ADVANCED_FACE('F631',(#788),#782,.T.);
#790=CARTESIAN_POINT('',(-771.604989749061,584.209465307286,-65.9929986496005));
#791=DIRECTION('',(0.,-1.,0.));
#792=DIRECTION('',(0.,0.,-1.));
#793=AXIS2_PLACEMENT_3D('',#790,#791,#792);
#794=CYLINDRICAL_SURFACE('',#793,2.54);
#795=ORIENTED_EDGE('',*,*,#99,.F.);
#796=ORIENTED_EDGE('',*,*,#647,.F.);
#797=ORIENTED_EDGE('',*,*,#515,.F.);
#798=ORIENTED_EDGE('',*,*,#461,.F.);
#799=EDGE_LOOP('',(#795,#796,#797,#798));
#800=FACE_BOUND('',#799,.T.);
#801=ADVANCED_FACE('F709',(#800),#794,.T.);
#802=CARTESIAN_POINT('',(-761.598172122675,606.797770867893,-60.9129986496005));
#803=DIRECTION('',(0.,-1.,0.));
#804=DIRECTION('',(0.,0.,-1.));
#805=AXIS2_PLACEMENT_3D('',#802,#803,#804);
#806=CYLINDRICAL_SURFACE('',#805,2.54);
#807=ORIENTED_EDGE('',*,*,#116,.F.);
#808=ORIENTED_EDGE('',*,*,#475,.F.);
#809=ORIENTED_EDGE('',*,*,#608,.F.);
#810=ORIENTED_EDGE('',*,*,#730,.F.);
#811=EDGE_LOOP('',(#807,#808,#809,#810));
#812=FACE_BOUND('',#811,.T.);
#813=ADVANCED_FACE('F594',(#812),#806,.F.);
#814=CARTESIAN_POINT('',(-726.128429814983,561.091856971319,-19.5198999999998));
#815=DIRECTION('',(0.,-1.,0.));
#816=DIRECTION('',(0.,0.,-1.));
#817=AXIS2_PLACEMENT_3D('',#814,#815,#816);
#818=CYLINDRICAL_SURFACE('',#817,2.05000000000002);
#819=CARTESIAN_POINT('',(-726.128429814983,550.017456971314,-19.5198999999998));
#820=DIRECTION('',(0.,-1.,0.));
#821=DIRECTION('',(0.,0.,-1.));
#822=AXIS2_PLACEMENT_3D('',#819,#820,#821);
#823=CIRCLE('',#822,2.05000000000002);
#824=CARTESIAN_POINT('',(-726.128429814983,550.017456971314,-21.5698999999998));
#825=VERTEX_POINT('',#824);
#826=EDGE_CURVE('E103',#825,#825,#823,.T.);
#827=ORIENTED_EDGE('',*,*,#826,.T.);
#828=EDGE_LOOP('',(#827));
#829=FACE_BOUND('',#828,.T.);
#830=ORIENTED_EDGE('',*,*,#42,.T.);
#831=EDGE_LOOP('',(#830));
#832=FACE_BOUND('',#831,.T.);
#833=ADVANCED_FACE('F568',(#829,#832),#818,.F.);
#834=CARTESIAN_POINT('',(-726.128429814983,561.091856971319,-58.5596999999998));
#835=DIRECTION('',(0.,-1.,0.));
#836=DIRECTION('',(0.,0.,-1.));
#837=AXIS2_PLACEMENT_3D('',#834,#835,#836);
#838=CYLINDRICAL_SURFACE('',#837,2.05000000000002);
#839=CARTESIAN_POINT('',(-726.128429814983,550.017456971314,-58.5596999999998));
#840=DIRECTION('',(0.,-1.,0.));
#841=DIRECTION('',(0.,0.,-1.));
#842=AXIS2_PLACEMENT_3D('',#839,#840,#841);
#843=CIRCLE('',#842,2.05000000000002);
#844=CARTESIAN_POINT('',(-726.128429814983,550.017456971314,-60.6096999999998));
#845=VERTEX_POINT('',#844);
#846=EDGE_CURVE('E12',#845,#845,#843,.T.);
#847=ORIENTED_EDGE('',*,*,#846,.T.);
#848=EDGE_LOOP('',(#847));
#849=FACE_BOUND('',#848,.T.);
#850=ORIENTED_EDGE('',*,*,#31,.T.);
#851=EDGE_LOOP('',(#850));
#852=FACE_BOUND('',#851,.T.);
#853=ADVANCED_FACE('F574',(#849,#852),#838,.F.);
#854=CARTESIAN_POINT('',(-726.128429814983,548.747456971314,-19.5198999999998));
#855=DIRECTION('',(0.,-1.,0.));
#856=DIRECTION('',(0.,0.,-1.));
#857=AXIS2_PLACEMENT_3D('',#854,#855,#856);
#858=CONICAL_SURFACE('',#857,3.31999999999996,0.785398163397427);
#859=ORIENTED_EDGE('',*,*,#826,.F.);
#860=EDGE_LOOP('',(#859));
#861=FACE_BOUND('',#860,.T.);
#862=ORIENTED_EDGE('',*,*,#492,.F.);
#863=EDGE_LOOP('',(#862));
#864=FACE_BOUND('',#863,.T.);
#865=ADVANCED_FACE('F571',(#861,#864),#858,.F.);
#866=CARTESIAN_POINT('',(-726.128429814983,548.747456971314,-58.5596999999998));
#867=DIRECTION('',(0.,-1.,0.));
#868=DIRECTION('',(0.,0.,-1.));
#869=AXIS2_PLACEMENT_3D('',#866,#867,#868);
#870=CONICAL_SURFACE('',#869,3.31999999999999,0.785398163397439);
#871=ORIENTED_EDGE('',*,*,#846,.F.);
#872=EDGE_LOOP('',(#871));
#873=FACE_BOUND('',#872,.T.);
#874=ORIENTED_EDGE('',*,*,#503,.F.);
#875=EDGE_LOOP('',(#874));
#876=FACE_BOUND('',#875,.T.);
#877=ADVANCED_FACE('F97',(#873,#876),#870,.F.);
#878=CARTESIAN_POINT('',(-760.597799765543,554.919656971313,-5.08));
#879=DIRECTION('',(0.,0.,1.));
#880=DIRECTION('',(1.,0.,0.));
#881=AXIS2_PLACEMENT_3D('',#878,#879,#880);
#882=CYLINDRICAL_SURFACE('',#881,4.25450000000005);
#883=ORIENTED_EDGE('',*,*,#408,.F.);
#884=DIRECTION('',(0.,0.,1.));
#885=VECTOR('',#884,1.);
#886=CARTESIAN_POINT('',(-756.343299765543,554.919656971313,-5.08));
#887=LINE('',#886,#885);
#888=CARTESIAN_POINT('',(-756.343299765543,554.919656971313,-5.08));
#889=VERTEX_POINT('',#888);
#890=EDGE_CURVE('E411',#889,#398,#887,.T.);
#891=ORIENTED_EDGE('',*,*,#890,.F.);
#892=CARTESIAN_POINT('',(-760.597799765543,554.919656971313,-5.08));
#893=DIRECTION('',(0.,0.,1.));
#894=DIRECTION('',(1.,0.,0.));
#895=AXIS2_PLACEMENT_3D('',#892,#893,#894);
#896=CIRCLE('',#895,4.25450000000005);
#897=CARTESIAN_POINT('',(-764.852299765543,554.919656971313,-5.08));
#898=VERTEX_POINT('',#897);
#899=EDGE_CURVE('E400',#889,#898,#896,.F.);
#900=ORIENTED_EDGE('',*,*,#899,.T.);
#901=DIRECTION('',(0.,0.,1.));
#902=VECTOR('',#901,1.);
#903=CARTESIAN_POINT('',(-764.852299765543,554.919656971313,-5.08));
#904=LINE('',#903,#902);
#905=EDGE_CURVE('E384',#898,#407,#904,.T.);
#906=ORIENTED_EDGE('',*,*,#905,.T.);
#907=EDGE_LOOP('',(#883,#891,#900,#906));
#908=FACE_BOUND('',#907,.T.);
#909=ADVANCED_FACE('F675',(#908),#882,.F.);
#910=CARTESIAN_POINT('',(-764.852299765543,0.,-5.08));
#911=DIRECTION('',(1.,0.,0.));
#912=DIRECTION('',(0.,0.,-1.));
#913=AXIS2_PLACEMENT_3D('',#910,#911,#912);
#914=PLANE('',#913);
#915=ORIENTED_EDGE('',*,*,#414,.F.);
#916=ORIENTED_EDGE('',*,*,#905,.F.);
#917=DIRECTION('',(0.,1.,0.));
#918=VECTOR('',#917,1.);
#919=CARTESIAN_POINT('',(-764.852299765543,0.,-5.08));
#920=LINE('',#919,#918);
#921=EDGE_CURVE('E409',#898,#203,#920,.T.);
#922=ORIENTED_EDGE('',*,*,#921,.T.);
#923=ORIENTED_EDGE('',*,*,#204,.T.);
#924=EDGE_LOOP('',(#915,#916,#922,#923));
#925=FACE_BOUND('',#924,.T.);
#926=ADVANCED_FACE('F677',(#925),#914,.T.);
#927=CARTESIAN_POINT('',(-756.343299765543,0.,-5.08));
#928=DIRECTION('',(-1.,0.,0.));
#929=DIRECTION('',(0.,0.,1.));
#930=AXIS2_PLACEMENT_3D('',#927,#928,#929);
#931=PLANE('',#930);
#932=ORIENTED_EDGE('',*,*,#399,.F.);
#933=ORIENTED_EDGE('',*,*,#220,.F.);
#934=DIRECTION('',(0.,-1.,0.));
#935=VECTOR('',#934,1.);
#936=CARTESIAN_POINT('',(-756.343299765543,0.,-5.08));
#937=LINE('',#936,#935);
#938=EDGE_CURVE('E403',#211,#889,#937,.T.);
#939=ORIENTED_EDGE('',*,*,#938,.T.);
#940=ORIENTED_EDGE('',*,*,#890,.T.);
#941=EDGE_LOOP('',(#932,#933,#939,#940));
#942=FACE_BOUND('',#941,.T.);
#943=ADVANCED_FACE('F668',(#942),#931,.T.);
#944=CARTESIAN_POINT('',(0.,0.,-5.08));
#945=DIRECTION('',(0.,0.,1.));
#946=DIRECTION('',(1.,0.,0.));
#947=AXIS2_PLACEMENT_3D('',#944,#945,#946);
#948=PLANE('',#947);
#949=ORIENTED_EDGE('',*,*,#899,.F.);
#950=ORIENTED_EDGE('',*,*,#938,.F.);
#951=ORIENTED_EDGE('',*,*,#212,.T.);
#952=ORIENTED_EDGE('',*,*,#921,.F.);
#953=EDGE_LOOP('',(#949,#950,#951,#952));
#954=FACE_BOUND('',#953,.T.);
#955=ADVANCED_FACE('F672',(#954),#948,.T.);
#956=CARTESIAN_POINT('',(-733.503419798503,554.919656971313,-5.08));
#957=DIRECTION('',(0.,0.,1.));
#958=DIRECTION('',(1.,0.,0.));
#959=AXIS2_PLACEMENT_3D('',#956,#957,#958);
#960=CYLINDRICAL_SURFACE('',#959,4.25450000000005);
#961=ORIENTED_EDGE('',*,*,#384,.F.);
#962=DIRECTION('',(0.,0.,1.));
#963=VECTOR('',#962,1.);
#964=CARTESIAN_POINT('',(-729.248919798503,554.919656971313,-5.08));
#965=LINE('',#964,#963);
#966=CARTESIAN_POINT('',(-729.248919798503,554.919656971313,-5.08));
#967=VERTEX_POINT('',#966);
#968=EDGE_CURVE('E379',#967,#381,#965,.T.);
#969=ORIENTED_EDGE('',*,*,#968,.F.);
#970=CARTESIAN_POINT('',(-733.503419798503,554.919656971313,-5.08));
#971=DIRECTION('',(0.,0.,1.));
#972=DIRECTION('',(1.,0.,0.));
#973=AXIS2_PLACEMENT_3D('',#970,#971,#972);
#974=CIRCLE('',#973,4.25450000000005);
#975=CARTESIAN_POINT('',(-737.757919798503,554.919656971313,-5.08));
#976=VERTEX_POINT('',#975);
#977=EDGE_CURVE('E368',#967,#976,#974,.F.);
#978=ORIENTED_EDGE('',*,*,#977,.T.);
#979=DIRECTION('',(0.,0.,1.));
#980=VECTOR('',#979,1.);
#981=CARTESIAN_POINT('',(-737.757919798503,554.919656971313,-5.08));
#982=LINE('',#981,#980);
#983=EDGE_CURVE('E389',#976,#383,#982,.T.);
#984=ORIENTED_EDGE('',*,*,#983,.T.);
#985=EDGE_LOOP('',(#961,#969,#978,#984));
#986=FACE_BOUND('',#985,.T.);
#987=ADVANCED_FACE('F659',(#986),#960,.F.);
#988=CARTESIAN_POINT('',(-737.757919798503,0.,-5.08));
#989=DIRECTION('',(1.,0.,0.));
#990=DIRECTION('',(0.,0.,-1.));
#991=AXIS2_PLACEMENT_3D('',#988,#989,#990);
#992=PLANE('',#991);
#993=ORIENTED_EDGE('',*,*,#390,.F.);
#994=ORIENTED_EDGE('',*,*,#983,.F.);
#995=DIRECTION('',(0.,1.,0.));
#996=VECTOR('',#995,1.);
#997=CARTESIAN_POINT('',(-737.757919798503,0.,-5.08));
#998=LINE('',#997,#996);
#999=EDGE_CURVE('E377',#976,#231,#998,.T.);
#1000=ORIENTED_EDGE('',*,*,#999,.T.);
#1001=ORIENTED_EDGE('',*,*,#232,.T.);
#1002=EDGE_LOOP('',(#993,#994,#1000,#1001));
#1003=FACE_BOUND('',#1002,.T.);
#1004=ADVANCED_FACE('F661',(#1003),#992,.T.);
#1005=CARTESIAN_POINT('',(-729.248919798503,0.,-5.08));
#1006=DIRECTION('',(-1.,0.,0.));
#1007=DIRECTION('',(0.,0.,1.));
#1008=AXIS2_PLACEMENT_3D('',#1005,#1006,#1007);
#1009=PLANE('',#1008);
#1010=ORIENTED_EDGE('',*,*,#444,.F.);
#1011=ORIENTED_EDGE('',*,*,#248,.F.);
#1012=DIRECTION('',(0.,-1.,0.));
#1013=VECTOR('',#1012,1.);
#1014=CARTESIAN_POINT('',(-729.248919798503,0.,-5.08));
#1015=LINE('',#1014,#1013);
#1016=EDGE_CURVE('E371',#239,#967,#1015,.T.);
#1017=ORIENTED_EDGE('',*,*,#1016,.T.);
#1018=ORIENTED_EDGE('',*,*,#968,.T.);
#1019=EDGE_LOOP('',(#1010,#1011,#1017,#1018));
#1020=FACE_BOUND('',#1019,.T.);
#1021=ADVANCED_FACE('F652',(#1020),#1009,.T.);
#1022=CARTESIAN_POINT('',(0.,0.,-5.08));
#1023=DIRECTION('',(0.,0.,1.));
#1024=DIRECTION('',(1.,0.,0.));
#1025=AXIS2_PLACEMENT_3D('',#1022,#1023,#1024);
#1026=PLANE('',#1025);
#1027=ORIENTED_EDGE('',*,*,#977,.F.);
#1028=ORIENTED_EDGE('',*,*,#1016,.F.);
#1029=ORIENTED_EDGE('',*,*,#240,.T.);
#1030=ORIENTED_EDGE('',*,*,#999,.F.);
#1031=EDGE_LOOP('',(#1027,#1028,#1029,#1030));
#1032=FACE_BOUND('',#1031,.T.);
#1033=ADVANCED_FACE('F656',(#1032),#1026,.T.);
#1034=CARTESIAN_POINT('',(-733.605019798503,554.919656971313,-72.9996));
#1035=DIRECTION('',(0.,0.,-1.));
#1036=DIRECTION('',(-1.,0.,0.));
#1037=AXIS2_PLACEMENT_3D('',#1034,#1035,#1036);
#1038=CYLINDRICAL_SURFACE('',#1037,4.25450000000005);
#1039=ORIENTED_EDGE('',*,*,#329,.F.);
#1040=DIRECTION('',(0.,0.,-1.));
#1041=VECTOR('',#1040,1.);
#1042=CARTESIAN_POINT('',(-737.859519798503,554.919656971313,-72.9996));
#1043=LINE('',#1042,#1041);
#1044=CARTESIAN_POINT('',(-737.859519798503,554.919656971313,-72.9996));
#1045=VERTEX_POINT('',#1044);
#1046=EDGE_CURVE('E354',#1045,#319,#1043,.T.);
#1047=ORIENTED_EDGE('',*,*,#1046,.F.);
#1048=CARTESIAN_POINT('',(-733.605019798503,554.919656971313,-72.9996));
#1049=DIRECTION('',(0.,0.,-1.));
#1050=DIRECTION('',(-1.,0.,0.));
#1051=AXIS2_PLACEMENT_3D('',#1048,#1049,#1050);
#1052=CIRCLE('',#1051,4.25450000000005);
#1053=CARTESIAN_POINT('',(-729.350519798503,554.919656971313,-72.9996));
#1054=VERTEX_POINT('',#1053);
#1055=EDGE_CURVE('E343',#1045,#1054,#1052,.F.);
#1056=ORIENTED_EDGE('',*,*,#1055,.T.);
#1057=DIRECTION('',(0.,0.,-1.));
#1058=VECTOR('',#1057,1.);
#1059=CARTESIAN_POINT('',(-729.350519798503,554.919656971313,-72.9996));
#1060=LINE('',#1059,#1058);
#1061=EDGE_CURVE('E335',#1054,#328,#1060,.T.);
#1062=ORIENTED_EDGE('',*,*,#1061,.T.);
#1063=EDGE_LOOP('',(#1039,#1047,#1056,#1062));
#1064=FACE_BOUND('',#1063,.T.);
#1065=ADVANCED_FACE('F805',(#1064),#1038,.F.);
#1066=CARTESIAN_POINT('',(-729.350519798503,0.,-72.9996));
#1067=DIRECTION('',(-1.,0.,0.));
#1068=DIRECTION('',(0.,0.,1.));
#1069=AXIS2_PLACEMENT_3D('',#1066,#1067,#1068);
#1070=PLANE('',#1069);
#1071=ORIENTED_EDGE('',*,*,#335,.F.);
#1072=ORIENTED_EDGE('',*,*,#1061,.F.);
#1073=DIRECTION('',(0.,1.,0.));
#1074=VECTOR('',#1073,1.);
#1075=CARTESIAN_POINT('',(-729.350519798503,0.,-72.9996));
#1076=LINE('',#1075,#1074);
#1077=EDGE_CURVE('E352',#1054,#271,#1076,.T.);
#1078=ORIENTED_EDGE('',*,*,#1077,.T.);
#1079=ORIENTED_EDGE('',*,*,#272,.T.);
#1080=EDGE_LOOP('',(#1071,#1072,#1078,#1079));
#1081=FACE_BOUND('',#1080,.T.);
#1082=ADVANCED_FACE('F939',(#1081),#1070,.T.);
#1083=CARTESIAN_POINT('',(-737.859519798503,0.,-72.9996));
#1084=DIRECTION('',(1.,0.,0.));
#1085=DIRECTION('',(0.,0.,-1.));
#1086=AXIS2_PLACEMENT_3D('',#1083,#1084,#1085);
#1087=PLANE('',#1086);
#1088=ORIENTED_EDGE('',*,*,#320,.F.);
#1089=ORIENTED_EDGE('',*,*,#286,.F.);
#1090=DIRECTION('',(0.,-1.,0.));
#1091=VECTOR('',#1090,1.);
#1092=CARTESIAN_POINT('',(-737.859519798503,0.,-72.9996));
#1093=LINE('',#1092,#1091);
#1094=EDGE_CURVE('E346',#279,#1045,#1093,.T.);
#1095=ORIENTED_EDGE('',*,*,#1094,.T.);
#1096=ORIENTED_EDGE('',*,*,#1046,.T.);
#1097=EDGE_LOOP('',(#1088,#1089,#1095,#1096));
#1098=FACE_BOUND('',#1097,.T.);
#1099=ADVANCED_FACE('F948',(#1098),#1087,.T.);
#1100=CARTESIAN_POINT('',(0.,0.,-72.9996));
#1101=DIRECTION('',(0.,0.,-1.));
#1102=DIRECTION('',(-1.,0.,0.));
#1103=AXIS2_PLACEMENT_3D('',#1100,#1101,#1102);
#1104=PLANE('',#1103);
#1105=ORIENTED_EDGE('',*,*,#1055,.F.);
#1106=ORIENTED_EDGE('',*,*,#1094,.F.);
#1107=ORIENTED_EDGE('',*,*,#280,.T.);
#1108=ORIENTED_EDGE('',*,*,#1077,.F.);
#1109=EDGE_LOOP('',(#1105,#1106,#1107,#1108));
#1110=FACE_BOUND('',#1109,.T.);
#1111=ADVANCED_FACE('F958',(#1110),#1104,.T.);
#1112=CARTESIAN_POINT('',(-760.699399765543,554.919656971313,-72.9996));
#1113=DIRECTION('',(0.,0.,-1.));
#1114=DIRECTION('',(-1.,0.,0.));
#1115=AXIS2_PLACEMENT_3D('',#1112,#1113,#1114);
#1116=CYLINDRICAL_SURFACE('',#1115,4.25450000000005);
#1117=ORIENTED_EDGE('',*,*,#305,.F.);
#1118=DIRECTION('',(0.,0.,-1.));
#1119=VECTOR('',#1118,1.);
#1120=CARTESIAN_POINT('',(-764.953899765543,554.919656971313,-72.9996));
#1121=LINE('',#1120,#1119);
#1122=CARTESIAN_POINT('',(-764.953899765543,554.919656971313,-72.9996));
#1123=VERTEX_POINT('',#1122);
#1124=EDGE_CURVE('E309',#1123,#302,#1121,.T.);
#1125=ORIENTED_EDGE('',*,*,#1124,.F.);
#1126=CARTESIAN_POINT('',(-760.699399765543,554.919656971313,-72.9996));
#1127=DIRECTION('',(0.,0.,-1.));
#1128=DIRECTION('',(-1.,0.,0.));
#1129=AXIS2_PLACEMENT_3D('',#1126,#1127,#1128);
#1130=CIRCLE('',#1129,4.25450000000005);
#1131=CARTESIAN_POINT('',(-756.444899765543,554.919656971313,-72.9996));
#1132=VERTEX_POINT('',#1131);
#1133=EDGE_CURVE('E318',#1123,#1132,#1130,.F.);
#1134=ORIENTED_EDGE('',*,*,#1133,.T.);
#1135=DIRECTION('',(0.,0.,-1.));
#1136=VECTOR('',#1135,1.);
#1137=CARTESIAN_POINT('',(-756.444899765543,554.919656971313,-72.9996));
#1138=LINE('',#1137,#1136);
#1139=EDGE_CURVE('E337',#1132,#304,#1138,.T.);
#1140=ORIENTED_EDGE('',*,*,#1139,.T.);
#1141=EDGE_LOOP('',(#1117,#1125,#1134,#1140));
#1142=FACE_BOUND('',#1141,.T.);
#1143=ADVANCED_FACE('F321',(#1142),#1116,.F.);
#1144=CARTESIAN_POINT('',(-756.444899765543,0.,-72.9996));
#1145=DIRECTION('',(-1.,0.,0.));
#1146=DIRECTION('',(0.,0.,1.));
#1147=AXIS2_PLACEMENT_3D('',#1144,#1145,#1146);
#1148=PLANE('',#1147);
#1149=ORIENTED_EDGE('',*,*,#311,.F.);
#1150=ORIENTED_EDGE('',*,*,#1139,.F.);
#1151=DIRECTION('',(0.,1.,0.));
#1152=VECTOR('',#1151,1.);
#1153=CARTESIAN_POINT('',(-756.444899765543,0.,-72.9996));
#1154=LINE('',#1153,#1152);
#1155=EDGE_CURVE('E323',#1132,#61,#1154,.T.);
#1156=ORIENTED_EDGE('',*,*,#1155,.T.);
#1157=ORIENTED_EDGE('',*,*,#62,.T.);
#1158=EDGE_LOOP('',(#1149,#1150,#1156,#1157));
#1159=FACE_BOUND('',#1158,.T.);
#1160=ADVANCED_FACE('F977',(#1159),#1148,.T.);
#1161=CARTESIAN_POINT('',(-764.953899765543,0.,-72.9996));
#1162=DIRECTION('',(1.,0.,0.));
#1163=DIRECTION('',(0.,0.,-1.));
#1164=AXIS2_PLACEMENT_3D('',#1161,#1162,#1163);
#1165=PLANE('',#1164);
#1166=ORIENTED_EDGE('',*,*,#365,.F.);
#1167=ORIENTED_EDGE('',*,*,#78,.F.);
#1168=DIRECTION('',(0.,-1.,0.));
#1169=VECTOR('',#1168,1.);
#1170=CARTESIAN_POINT('',(-764.953899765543,0.,-72.9996));
#1171=LINE('',#1170,#1169);
#1172=EDGE_CURVE('E307',#69,#1123,#1171,.T.);
#1173=ORIENTED_EDGE('',*,*,#1172,.T.);
#1174=ORIENTED_EDGE('',*,*,#1124,.T.);
#1175=EDGE_LOOP('',(#1166,#1167,#1173,#1174));
#1176=FACE_BOUND('',#1175,.T.);
#1177=ADVANCED_FACE('F308',(#1176),#1165,.T.);
#1178=CARTESIAN_POINT('',(0.,0.,-72.9996));
#1179=DIRECTION('',(0.,0.,-1.));
#1180=DIRECTION('',(-1.,0.,0.));
#1181=AXIS2_PLACEMENT_3D('',#1178,#1179,#1180);
#1182=PLANE('',#1181);
#1183=ORIENTED_EDGE('',*,*,#1133,.F.);
#1184=ORIENTED_EDGE('',*,*,#1172,.F.);
#1185=ORIENTED_EDGE('',*,*,#70,.T.);
#1186=ORIENTED_EDGE('',*,*,#1155,.F.);
#1187=EDGE_LOOP('',(#1183,#1184,#1185,#1186));
#1188=FACE_BOUND('',#1187,.T.);
#1189=ADVANCED_FACE('F325',(#1188),#1182,.T.);
#1190=CLOSED_SHELL('',(#290,#369,#448,#479,#612,#629,#641,#653,#675,#697,#719,#741,#753,#765,
#777,#789,#801,#813,#833,#853,#865,#877,#909,#926,#943,#955,#987,#1004,#1021,#1033,#1065,#1082,
#1099,#1111,#1143,#1160,#1177,#1189));
#1191=MANIFOLD_SOLID_BREP('B2',#1190);
#1192=ADVANCED_BREP_SHAPE_REPRESENTATION('',(#18,#1191),#14);
#1193=SHAPE_DEFINITION_REPRESENTATION(#9,#1192);
ENDSEC;
END-ISO-10303-21;
